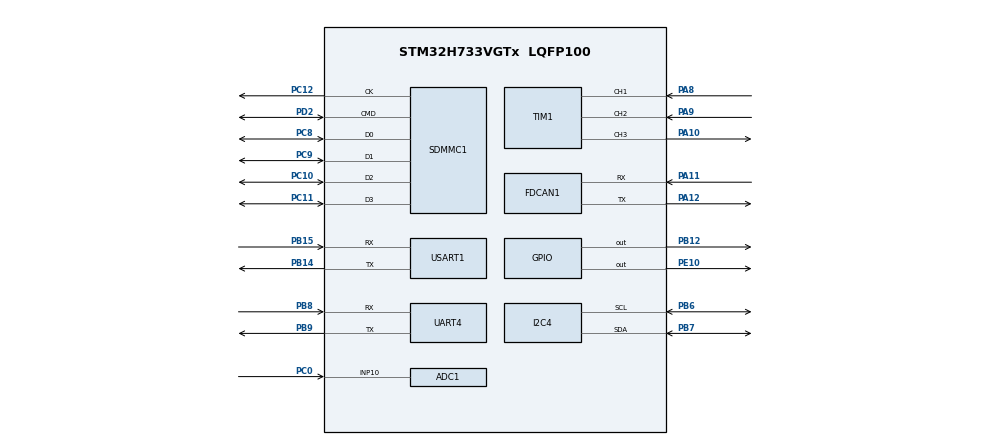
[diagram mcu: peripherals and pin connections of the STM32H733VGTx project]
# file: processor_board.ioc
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ADC1.Channel-1\#ChannelRegularConversion=ADC_CHANNEL_10
ADC1.NbrOfConversion=1
ADC1.NbrOfConversionFlag=1
ADC1.OffsetNumber-1\#ChannelRegularConversion=ADC_OFFSET_NONE
ADC1.OffsetSignedSaturation-1\#ChannelRegularConversion=DISABLE
ADC1.Rank-1\#ChannelRegularConversion=1
ADC1.SamplingTime-1\#ChannelRegularConversion=ADC_SAMPLETIME_1CYCLE_5
ADC1.master=1
Dma.Request0=USART1_RX
Dma.USART1_RX.0.Direction=DMA_PERIPH_TO_MEMORY
Dma.USART1_RX.0.EventEnable=DISABLE
Dma.USART1_RX.0.FIFOMode=DMA_FIFOMODE_DISABLE
Dma.USART1_RX.0.Instance=DMA1_Stream0
Dma.USART1_RX.0.MemDataAlignment=DMA_MDATAALIGN_BYTE
Dma.USART1_RX.0.MemInc=DMA_MINC_ENABLE
Dma.USART1_RX.0.Mode=DMA_NORMAL
Dma.USART1_RX.0.PeriphDataAlignment=DMA_PDATAALIGN_BYTE
Dma.USART1_RX.0.PeriphInc=DMA_PINC_DISABLE
Dma.USART1_RX.0.Polarity=HAL_DMAMUX_REQ_GEN_RISING
Dma.USART1_RX.0.Priority=DMA_PRIORITY_LOW
Dma.USART1_RX.0.RequestNumber=1
Dma.USART1_RX.0.SignalID=NONE
Dma.USART1_RX.0.SyncEnable=DISABLE
Dma.USART1_RX.0.SyncPolarity=HAL_DMAMUX_SYNC_NO_EVENT
Dma.USART1_RX.0.SyncRequestNumber=1
Dma.USART1_RX.0.SyncSignalID=NONE
FDCAN1.CalculateBaudRateNominal=1500000
FDCAN1.CalculateTimeBitNominal=666
FDCAN1.CalculateTimeQuantumNominal=83.33333333333333
FDCAN1.DataPrescaler=4
FDCAN1.DataSyncJumpWidth=4
FDCAN1.DataTimeSeg1=4
FDCAN1.DataTimeSeg2=3
FDCAN1.NominalPrescaler=4
FDCAN1.NominalSyncJumpWidth=4
FDCAN1.NominalTimeSeg1=4
FDCAN1.NominalTimeSeg2=3
FDCAN1.RxFifo0ElmtsNbr=64
FDCAN1.StdFiltersNbr=0
FDCAN1.TxEventsNbr=32
FDCAN1.TxFifoQueueElmtsNbr=32
FREERTOS.INCLUDE_xEventGroupSetBitFromISR=1
FREERTOS.Tasks01=defaultTaskaaa,24,512,StartDefaultTask,Default,NULL,Dynamic,NULL,NULL
FREERTOS.configCHECK_FOR_STACK_OVERFLOW=1
FREERTOS.configENABLE_FPU=1
FREERTOS.configTIMER_TASK_PRIORITY=55
FREERTOS.configTOTAL_HEAP_SIZE=131072
FREERTOS.configUSE_NEWLIB_REENTRANT=0
I2C4.Timing=0x009095E1
Mcu.Family=STM32H7
Mcu.Name=STM32H733VGTx
Mcu.Package=LQFP100
NVIC.DMA1_Stream0_IRQn=true\:5\:0\:false\:false\:true\:true\:false\:true\:true
NVIC.FDCAN1_IT0_IRQn=true\:5\:0\:false\:false\:true\:true\:true\:true\:true
NVIC.I2C4_ER_IRQn=true\:5\:0\:false\:false\:true\:true\:true\:true\:true
NVIC.I2C4_EV_IRQn=true\:5\:0\:false\:false\:true\:true\:true\:true\:true
NVIC.PriorityGroup=NVIC_PRIORITYGROUP_4
NVIC.SDMMC1_IRQn=true\:5\:0\:false\:false\:true\:true\:true\:true\:true
NVIC.TIM6_DAC_IRQn=true\:15\:0\:false\:false\:true\:false\:false\:true\:true
NVIC.TimeBase=TIM6_DAC_IRQn
NVIC.TimeBaseIP=TIM6
NVIC.USART1_IRQn=true\:5\:0\:false\:false\:true\:true\:true\:true\:true
PA10.Signal=S_TIM1_CH3
PA11.GPIO_Speed=GPIO_SPEED_FREQ_LOW
PA11.Mode=FDCAN_Activate
PA11.Signal=FDCAN1_RX
PA12.Mode=FDCAN_Activate
PA12.Signal=FDCAN1_TX
PA13(JTMS/SWDIO).Mode=Serial_Wire
PA13(JTMS/SWDIO).Signal=DEBUG_JTMS-SWDIO
PA14(JTCK/SWCLK).Mode=Serial_Wire
PA14(JTCK/SWCLK).Signal=DEBUG_JTCK-SWCLK
PA8.Signal=S_TIM1_CH1
PA9.Signal=S_TIM1_CH2
PB12.Signal=GPIO_Output
PB14.Mode=Asynchronous
PB14.Signal=USART1_TX
PB15.Mode=Asynchronous
PB15.Signal=USART1_RX
PB6.Mode=I2C
PB6.Signal=I2C4_SCL
PB7.Mode=I2C
PB7.Signal=I2C4_SDA
PB8.Mode=Asynchronous
PB8.Signal=UART4_RX
PB9.Mode=Asynchronous
PB9.Signal=UART4_TX
PC0.Signal=ADCx_INP10
PC10.Mode=SD_4_bits_Wide_bus
PC10.Signal=SDMMC1_D2
PC11.Mode=SD_4_bits_Wide_bus
PC11.Signal=SDMMC1_D3
PC12.Mode=SD_4_bits_Wide_bus
PC12.Signal=SDMMC1_CK
PC8.Mode=SD_4_bits_Wide_bus
PC8.Signal=SDMMC1_D0
PC9.Mode=SD_4_bits_Wide_bus
PC9.Signal=SDMMC1_D1
PD2.Mode=SD_4_bits_Wide_bus
PD2.Signal=SDMMC1_CMD
PE10.Signal=GPIO_Output
PH0-OSC_IN.Mode=HSE-External-Clock-Source
PH0-OSC_IN.Signal=RCC_OSC_IN
ProjectManager.HeapSize=0x200
ProjectManager.StackSize=0x400
ProjectManager.TargetToolchain=STM32CubeIDE
RCC.ADCFreq_Value=38400000
RCC.APB1Freq_Value=96000000
RCC.APB2Freq_Value=96000000
RCC.APB3Freq_Value=96000000
RCC.APB4Freq_Value=96000000
RCC.CortexFreq_Value=192000000
RCC.D1PPRE=RCC_APB3_DIV2
RCC.D2PPRE1=RCC_APB1_DIV2
RCC.D2PPRE2=RCC_APB2_DIV2
RCC.D3PPRE=RCC_APB4_DIV2
RCC.DIVM1=1
RCC.DIVM2=1
RCC.DIVM3=1
RCC.DIVN1=48
RCC.DIVN2=48
RCC.DIVN3=48
RCC.DIVP1=1
RCC.DIVP2=5
RCC.DIVQ1=3
RCC.DIVQ2=4
RCC.DIVQ3=5
RCC.DIVR1=4
RCC.DIVR3=5
RCC.FDCANCLockSelection=RCC_FDCANCLKSOURCE_PLL2
RCC.HCLKFreq_Value=192000000
RCC.HSE_VALUE=4000000
RCC.I2C4CLockSelection=RCC_I2C4CLKSOURCE_PLL3
RCC.PLL2FRACN=0
RCC.PLL3FRACN=0
RCC.PLLFRACN=0
RCC.PLLSourceVirtual=RCC_PLLSOURCE_HSE
RCC.RCC_RTC_Clock_Source_FROM_HSE=RCC_RTCCLKSOURCE_HSE_DIV32
RCC.RTCClockSelection=RCC_RTCCLKSOURCE_HSE_DIV32
RCC.SYSCLKFreq_VALUE=192000000
RCC.SYSCLKSource=RCC_SYSCLKSOURCE_PLLCLK
RCC.USART16CLockSelection=RCC_USART16910CLKSOURCE_PLL3
RCC.USART234578CLockSelection=RCC_USART234578CLKSOURCE_PLL3
RCC.USBFreq_Value=64000000
SH.ADCx_INP10.0=ADC1_INP10,IN10-Single-Ended
SH.S_TIM1_CH1.0=TIM1_CH1,Input_Capture1_from_TI1
SH.S_TIM1_CH2.0=TIM1_CH2,Input_Capture2_from_TI2
SH.S_TIM1_CH3.0=TIM1_CH3,PWM Generation3 CH3
TIM1.Channel-Input_Capture1_from_TI1=TIM_CHANNEL_1
TIM1.Channel-Input_Capture2_from_TI2=TIM_CHANNEL_2
TIM1.Channel-PWM\ Generation3\ CH3=TIM_CHANNEL_3
TIM2.Prescaler=12500
UART4.SwapParam=UART_ADVFEATURE_SWAP_ENABLE
USART1.OverrunDisableParam=ADVFEATURE_OVERRUN_DISABLE
USART1.VirtualMode-Asynchronous=VM_ASYNC
VP_CORDIC_VS_CORDIC.Mode=CORDIC_Activate
VP_FATFS_VS_SDIO.Mode=SDIO
VP_FMAC_VS_FMAC.Mode=FMAC_Activate
VP_FREERTOS_VS_CMSIS_V2.Mode=CMSIS_V2
VP_MEMORYMAP_VS_MEMORYMAP.Mode=CurAppReg
VP_RTC_VS_RTC_Activate.Mode=RTC_Enabled
VP_SYS_VS_tim6.Mode=TIM6
VP_TIM1_VS_ClockSourceINT.Mode=Internal
VP_TIM2_VS_ClockSourceINT.Mode=Internal
VREF+.Mode=InternalMode
VREF+.Signal=VREFBUF_OUT
board=custom

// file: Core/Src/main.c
/* USER CODE BEGIN Header */
/**
  ******************************************************************************
  * @file           : main.c
  * @brief          : Main program body
  ******************************************************************************
  * @attention
  *
  * Copyright (c) 2024 STMicroelectronics.
  * All rights reserved.
  *
  * This software is licensed under terms that can be found in the LICENSE file
  * in the root directory of this software component.
  * If no LICENSE file comes with this software, it is provided AS-IS.
  *
  ******************************************************************************
  */
/* USER CODE END Header */
#include "main.h"
#include "cmsis_os.h"
#include "fatfs.h"

/* USER CODE BEGIN Includes */
#include "printf.h"
//#include "canlib.h"
#include "millis.h"
//#include "ICM-20948.h"

#include "log.h"
//#include "controller.h"
//#include "flight_phase.h"
//#include "health_checks.h"
//#include "state_estimation.h"
//#include "trajectory.h"
#include "can_handler.h"
#include "otits.h"
//#include "sdmmc.h"
//#include "vn_handler.h"

#include "simulink_handler.h"
/* USER CODE END Includes */

/* USER CODE BEGIN PD */
#define DEFAULT_STACKDEPTH_WORDS 128 * 4
/* USER CODE END PD */

ADC_HandleTypeDef hadc1;

CORDIC_HandleTypeDef hcordic;

FDCAN_HandleTypeDef hfdcan1;

FMAC_HandleTypeDef hfmac;

I2C_HandleTypeDef hi2c4;

RTC_HandleTypeDef hrtc;

SD_HandleTypeDef hsd1;

TIM_HandleTypeDef htim1;
TIM_HandleTypeDef htim2;

UART_HandleTypeDef huart4;
UART_HandleTypeDef huart1;
DMA_HandleTypeDef hdma_usart1_rx;

/* Definitions for defaultTask */
osThreadId_t defaultTaskHandle;
const osThreadAttr_t defaultTask_attributes = {
  .name = "defaultTask",
  .stack_size = 512 * 4,
  .priority = (osPriority_t) osPriorityNormal,
};
/* USER CODE BEGIN PV */
uint32_t idx;

//Task handles
TaskHandle_t logTaskhandle = NULL;
TaskHandle_t VNTaskHandle = NULL;
TaskHandle_t trajectoryTaskHandle = NULL;
TaskHandle_t stateEstTaskHandle = NULL;
TaskHandle_t canhandlerhandle = NULL;
TaskHandle_t healthChecksTaskHandle = NULL;
TaskHandle_t controllerHandle = NULL;
TaskHandle_t flightPhaseHandle = NULL;
TaskHandle_t oTITSHandle = NULL;
TaskHandle_t updateModelHandle = NULL;

/* USER CODE END PV */

void SystemClock_Config(void);
void PeriphCommonClock_Config(void);
static void MX_GPIO_Init(void);
static void MX_DMA_Init(void);
static void MX_CORDIC_Init(void);
static void MX_FDCAN1_Init(void);
static void MX_FMAC_Init(void);
static void MX_I2C4_Init(void);
static void MX_RTC_Init(void);
static void MX_SDMMC1_SD_Init(void);
static void MX_UART4_Init(void);
static void MX_TIM1_Init(void);
static void MX_ADC1_Init(void);
static void MX_USART1_UART_Init(void);
static void MX_TIM2_Init(void);
void StartDefaultTask(void *argument);

/* USER CODE BEGIN 0 */
Otits_Result_t test_defaultTaskPass() {
	Otits_Result_t res;
	res.info = "this should pass";
	res.outcome = TEST_OUTCOME_PASSED;
	return res;
}

Otits_Result_t test_defaultTaskFail() {
	Otits_Result_t res;
	res.info = "this should fail";
	res.outcome = TEST_OUTCOME_FAILED;
	return res;
}

Otits_Result_t test_taskStackUsage() {
    Otits_Result_t res;
    const int numTasks = 9;
    int stackWatermarks[numTasks];

    stackWatermarks[0] = uxTaskGetStackHighWaterMark(logTaskhandle);
    stackWatermarks[1] = uxTaskGetStackHighWaterMark(VNTaskHandle);
    stackWatermarks[2] = uxTaskGetStackHighWaterMark(trajectoryTaskHandle);
    stackWatermarks[3] = uxTaskGetStackHighWaterMark(stateEstTaskHandle);
    stackWatermarks[4] = uxTaskGetStackHighWaterMark(canhandlerhandle);
    stackWatermarks[5] = uxTaskGetStackHighWaterMark(healthChecksTaskHandle);
    stackWatermarks[6] = uxTaskGetStackHighWaterMark(controllerHandle);
    stackWatermarks[7] = uxTaskGetStackHighWaterMark(flightPhaseHandle);
    stackWatermarks[8] = uxTaskGetStackHighWaterMark(oTITSHandle);

    for (int i = 0; i < numTasks; i++) {
        if (stackWatermarks[i] < 50) {
            char info[10];
            snprintf_(info, 10, "low%d", i);
            res.info = info;
            res.outcome = TEST_OUTCOME_FAILED;
            return res;
        } else if (stackWatermarks[i] > 1000) {
            char info[10];
            snprintf_(info, 10, "high%d", i);
            res.info = info;
            res.outcome = TEST_OUTCOME_FAILED;
            return res;
        }
    }

    res.info = "";
    res.outcome = TEST_OUTCOME_PASSED;
    return res;
}

/* USER CODE END 0 */

int main(void)
{

  /* MCU Configuration--------------------------------------------------------*/

  /* Reset of all peripherals, Initializes the Flash interface and the Systick. */
  HAL_Init();

  /* Configure the system clock */
  SystemClock_Config();

/* Configure the peripherals common clocks */
  PeriphCommonClock_Config();

  /* Initialize all configured peripherals */
  MX_GPIO_Init();
  MX_DMA_Init();
  MX_CORDIC_Init();
  MX_FDCAN1_Init();
  MX_FMAC_Init();
  MX_I2C4_Init();
  MX_RTC_Init();
  MX_SDMMC1_SD_Init();
  MX_UART4_Init();
  MX_FATFS_Init();
  MX_TIM1_Init();
  MX_ADC1_Init();
  MX_USART1_UART_Init();
  MX_TIM2_Init();
  /* USER CODE BEGIN 2 */
  HAL_TIM_Base_Start(&htim2);
  /* USER CODE END 2 */

  /* Init scheduler */
  osKernelInitialize();

  /* USER CODE BEGIN RTOS_QUEUES */
  bool initRes = true;
#if USE_ICM == 1
  ICM_20948_init();
#endif
//  initRes &= sdmmcInit();
//  initRes &= logInit();
//  initRes &= trajectory_init();
  initRes &= canHandlerInit(); //create bus queue
//  initRes &= flightPhaseInit();
//  initRes &= healthCheckInit();
//  initRes &= controllerInit();
//  initRes &= state_est_init();
//  initRes &= vn_handler_init();
  	updateModelTaskInit();

  // otits is ifdef guarded within itself so can leave these
  initRes &= otitsRegister(test_defaultTaskPass, TEST_SOURCE_DEFAULT, "DefaultPass");
  initRes &= otitsRegister(test_defaultTaskFail, TEST_SOURCE_DEFAULT, "DefaultFail");
  initRes &= otitsRegister(test_taskStackUsage, TEST_SOURCE_DEFAULT, "StackUsage");

  if (!initRes) {
      Error_Handler();
  }
  /* USER CODE END RTOS_QUEUES */

  /* Create the thread(s) */
  /* creation of defaultTask */
  defaultTaskHandle = osThreadNew(StartDefaultTask, NULL, &defaultTask_attributes);

  /* USER CODE BEGIN RTOS_THREADS */
  /* add threads, ... */
  BaseType_t xReturned = pdPASS;

  //dunno if casting from CMSIS priorities is valid
//  xReturned &= xTaskCreate(vnIMUHandler, "VN Task", 1024, NULL, (UBaseType_t) osPriorityNormal, &VNTaskHandle);
  xReturned &= xTaskCreate(canHandlerTask, "CAN handler", 512, NULL, (UBaseType_t) osPriorityNormal, &canhandlerhandle);
//  xReturned &= xTaskCreate(stateEstTask, "StateEst", 1024, NULL, (UBaseType_t) osPriorityNormal, &stateEstTaskHandle);
//  xReturned &= xTaskCreate(trajectory_task, "traj", 512, NULL, (UBaseType_t) osPriorityNormal, &trajectoryTaskHandle);
//  xReturned &= xTaskCreate(logTask, "Logging", 1024, NULL, (UBaseType_t) osPriorityNormal, &logTaskhandle);
//  xReturned &= xTaskCreate(healthCheckTask, "health checks", 512, NULL, (UBaseType_t) osPriorityNormal, &healthChecksTaskHandle);
//  xReturned &= xTaskCreate(controlTask, "Controller", 512, NULL, (UBaseType_t) osPriorityNormal, &controllerHandle);
//  xReturned &= xTaskCreate(flightPhaseTask, "Flight Phase", 512, NULL, (UBaseType_t) osPriorityNormal, &flightPhaseHandle);
  xReturned &= xTaskCreate(updateModelTask, "simulink", 512, NULL, (UBaseType_t) osPriorityNormal, &updateModelHandle);

#if  defined(TEST_MODE) && defined(DEBUG)
  xReturned &= xTaskCreate(otitsTask, "oTITS", 1024, NULL, (UBaseType_t) osPriorityNormal, &oTITSHandle);
#endif

  if(xReturned != pdPASS)
  {
	  //one or more tasks failed to be created
	  Error_Handler();
  }

  /* USER CODE END RTOS_THREADS */

  /* Start scheduler */
  osKernelStart();

  /* We should never get here as control is now taken by the scheduler */

  /* Infinite loop */
  while (1)
  {

  }
}

void SystemClock_Config(void)
{
  RCC_OscInitTypeDef RCC_OscInitStruct = {0};
  RCC_ClkInitTypeDef RCC_ClkInitStruct = {0};

  /** Supply configuration update enable
  */
  HAL_PWREx_ConfigSupply(PWR_LDO_SUPPLY);

  /** Configure the main internal regulator output voltage
  */
  __HAL_PWR_VOLTAGESCALING_CONFIG(PWR_REGULATOR_VOLTAGE_SCALE0);

  while(!__HAL_PWR_GET_FLAG(PWR_FLAG_VOSRDY)) {}

  /** Initializes the RCC Oscillators according to the specified parameters
  * in the RCC_OscInitTypeDef structure.
  */
  RCC_OscInitStruct.OscillatorType = RCC_OSCILLATORTYPE_HSE;
  RCC_OscInitStruct.HSEState = RCC_HSE_BYPASS;
  RCC_OscInitStruct.PLL.PLLState = RCC_PLL_ON;
  RCC_OscInitStruct.PLL.PLLSource = RCC_PLLSOURCE_HSE;
  RCC_OscInitStruct.PLL.PLLM = 1;
  RCC_OscInitStruct.PLL.PLLN = 125;
  RCC_OscInitStruct.PLL.PLLP = 1;
  RCC_OscInitStruct.PLL.PLLQ = 20;
  RCC_OscInitStruct.PLL.PLLR = 4;
  RCC_OscInitStruct.PLL.PLLRGE = RCC_PLL1VCIRANGE_2;
  RCC_OscInitStruct.PLL.PLLVCOSEL = RCC_PLL1VCOWIDE;
  RCC_OscInitStruct.PLL.PLLFRACN = 0;
  if (HAL_RCC_OscConfig(&RCC_OscInitStruct) != HAL_OK)
  {
    Error_Handler();
  }

  /** Initializes the CPU, AHB and APB buses clocks
  */
  RCC_ClkInitStruct.ClockType = RCC_CLOCKTYPE_HCLK|RCC_CLOCKTYPE_SYSCLK
                              |RCC_CLOCKTYPE_PCLK1|RCC_CLOCKTYPE_PCLK2
                              |RCC_CLOCKTYPE_D3PCLK1|RCC_CLOCKTYPE_D1PCLK1;
  RCC_ClkInitStruct.SYSCLKSource = RCC_SYSCLKSOURCE_PLLCLK;
  RCC_ClkInitStruct.SYSCLKDivider = RCC_SYSCLK_DIV1;
  RCC_ClkInitStruct.AHBCLKDivider = RCC_HCLK_DIV4;
  RCC_ClkInitStruct.APB3CLKDivider = RCC_APB3_DIV2;
  RCC_ClkInitStruct.APB1CLKDivider = RCC_APB1_DIV2;
  RCC_ClkInitStruct.APB2CLKDivider = RCC_APB2_DIV2;
  RCC_ClkInitStruct.APB4CLKDivider = RCC_APB4_DIV2;

  if (HAL_RCC_ClockConfig(&RCC_ClkInitStruct, FLASH_LATENCY_1) != HAL_OK)
  {
    Error_Handler();
  }
}

void PeriphCommonClock_Config(void)
{
  RCC_PeriphCLKInitTypeDef PeriphClkInitStruct = {0};

  /** Initializes the peripherals clock
  */
  PeriphClkInitStruct.PeriphClockSelection = RCC_PERIPHCLK_I2C4|RCC_PERIPHCLK_ADC
                              |RCC_PERIPHCLK_FDCAN|RCC_PERIPHCLK_USART1
                              |RCC_PERIPHCLK_UART4;
  PeriphClkInitStruct.PLL2.PLL2M = 1;
  PeriphClkInitStruct.PLL2.PLL2N = 120;
  PeriphClkInitStruct.PLL2.PLL2P = 20;
  PeriphClkInitStruct.PLL2.PLL2Q = 60;
  PeriphClkInitStruct.PLL2.PLL2R = 2;
  PeriphClkInitStruct.PLL2.PLL2RGE = RCC_PLL2VCIRANGE_2;
  PeriphClkInitStruct.PLL2.PLL2VCOSEL = RCC_PLL2VCOWIDE;
  PeriphClkInitStruct.PLL2.PLL2FRACN = 0;
  PeriphClkInitStruct.PLL3.PLL3M = 2;
  PeriphClkInitStruct.PLL3.PLL3N = 128;
  PeriphClkInitStruct.PLL3.PLL3P = 2;
  PeriphClkInitStruct.PLL3.PLL3Q = 2;
  PeriphClkInitStruct.PLL3.PLL3R = 8;
  PeriphClkInitStruct.PLL3.PLL3RGE = RCC_PLL3VCIRANGE_1;
  PeriphClkInitStruct.PLL3.PLL3VCOSEL = RCC_PLL3VCOWIDE;
  PeriphClkInitStruct.PLL3.PLL3FRACN = 0;
  PeriphClkInitStruct.FdcanClockSelection = RCC_FDCANCLKSOURCE_PLL2;
  PeriphClkInitStruct.Usart234578ClockSelection = RCC_USART234578CLKSOURCE_PLL3;
  PeriphClkInitStruct.Usart16ClockSelection = RCC_USART16910CLKSOURCE_PLL3;
  PeriphClkInitStruct.I2c4ClockSelection = RCC_I2C4CLKSOURCE_PLL3;
  PeriphClkInitStruct.AdcClockSelection = RCC_ADCCLKSOURCE_PLL2;
  if (HAL_RCCEx_PeriphCLKConfig(&PeriphClkInitStruct) != HAL_OK)
  {
    Error_Handler();
  }
}

static void MX_ADC1_Init(void)
{

  ADC_MultiModeTypeDef multimode = {0};
  ADC_ChannelConfTypeDef sConfig = {0};

  /** Common config
  */
  hadc1.Instance = ADC1;
  hadc1.Init.ClockPrescaler = ADC_CLOCK_ASYNC_DIV1;
  hadc1.Init.Resolution = ADC_RESOLUTION_16B;
  hadc1.Init.ScanConvMode = ADC_SCAN_DISABLE;
  hadc1.Init.EOCSelection = ADC_EOC_SINGLE_CONV;
  hadc1.Init.LowPowerAutoWait = DISABLE;
  hadc1.Init.ContinuousConvMode = DISABLE;
  hadc1.Init.NbrOfConversion = 1;
  hadc1.Init.DiscontinuousConvMode = DISABLE;
  hadc1.Init.ExternalTrigConv = ADC_SOFTWARE_START;
  hadc1.Init.ExternalTrigConvEdge = ADC_EXTERNALTRIGCONVEDGE_NONE;
  hadc1.Init.ConversionDataManagement = ADC_CONVERSIONDATA_DR;
  hadc1.Init.Overrun = ADC_OVR_DATA_PRESERVED;
  hadc1.Init.LeftBitShift = ADC_LEFTBITSHIFT_NONE;
  hadc1.Init.OversamplingMode = DISABLE;
  if (HAL_ADC_Init(&hadc1) != HAL_OK)
  {
    Error_Handler();
  }

  /** Configure the ADC multi-mode
  */
  multimode.Mode = ADC_MODE_INDEPENDENT;
  if (HAL_ADCEx_MultiModeConfigChannel(&hadc1, &multimode) != HAL_OK)
  {
    Error_Handler();
  }

  /** Configure Regular Channel
  */
  sConfig.Channel = ADC_CHANNEL_10;
  sConfig.Rank = ADC_REGULAR_RANK_1;
  sConfig.SamplingTime = ADC_SAMPLETIME_1CYCLE_5;
  sConfig.SingleDiff = ADC_SINGLE_ENDED;
  sConfig.OffsetNumber = ADC_OFFSET_NONE;
  sConfig.Offset = 0;
  sConfig.OffsetSignedSaturation = DISABLE;
  if (HAL_ADC_ConfigChannel(&hadc1, &sConfig) != HAL_OK)
  {
    Error_Handler();
  }

}

static void MX_CORDIC_Init(void)
{

  hcordic.Instance = CORDIC;
  if (HAL_CORDIC_Init(&hcordic) != HAL_OK)
  {
    Error_Handler();
  }

}

static void MX_FDCAN1_Init(void)
{

  hfdcan1.Instance = FDCAN1;
  hfdcan1.Init.FrameFormat = FDCAN_FRAME_CLASSIC;
  hfdcan1.Init.Mode = FDCAN_MODE_NORMAL;
  hfdcan1.Init.AutoRetransmission = DISABLE;
  hfdcan1.Init.TransmitPause = DISABLE;
  hfdcan1.Init.ProtocolException = DISABLE;
  hfdcan1.Init.NominalPrescaler = 4;
  hfdcan1.Init.NominalSyncJumpWidth = 4;
  hfdcan1.Init.NominalTimeSeg1 = 4;
  hfdcan1.Init.NominalTimeSeg2 = 3;
  hfdcan1.Init.DataPrescaler = 4;
  hfdcan1.Init.DataSyncJumpWidth = 4;
  hfdcan1.Init.DataTimeSeg1 = 4;
  hfdcan1.Init.DataTimeSeg2 = 3;
  hfdcan1.Init.MessageRAMOffset = 0;
  hfdcan1.Init.StdFiltersNbr = 0;
  hfdcan1.Init.ExtFiltersNbr = 0;
  hfdcan1.Init.RxFifo0ElmtsNbr = 64;
  hfdcan1.Init.RxFifo0ElmtSize = FDCAN_DATA_BYTES_8;
  hfdcan1.Init.RxFifo1ElmtsNbr = 0;
  hfdcan1.Init.RxFifo1ElmtSize = FDCAN_DATA_BYTES_8;
  hfdcan1.Init.RxBuffersNbr = 0;
  hfdcan1.Init.RxBufferSize = FDCAN_DATA_BYTES_8;
  hfdcan1.Init.TxEventsNbr = 32;
  hfdcan1.Init.TxBuffersNbr = 0;
  hfdcan1.Init.TxFifoQueueElmtsNbr = 32;
  hfdcan1.Init.TxFifoQueueMode = FDCAN_TX_FIFO_OPERATION;
  hfdcan1.Init.TxElmtSize = FDCAN_DATA_BYTES_8;
  if (HAL_FDCAN_Init(&hfdcan1) != HAL_OK)
  {
    Error_Handler();
  }

}

static void MX_FMAC_Init(void)
{

  hfmac.Instance = FMAC;
  if (HAL_FMAC_Init(&hfmac) != HAL_OK)
  {
    Error_Handler();
  }

}

static void MX_I2C4_Init(void)
{

  hi2c4.Instance = I2C4;
  hi2c4.Init.Timing = 0x00707CBB;
  hi2c4.Init.OwnAddress1 = 0;
  hi2c4.Init.AddressingMode = I2C_ADDRESSINGMODE_7BIT;
  hi2c4.Init.DualAddressMode = I2C_DUALADDRESS_DISABLE;
  hi2c4.Init.OwnAddress2 = 0;
  hi2c4.Init.OwnAddress2Masks = I2C_OA2_NOMASK;
  hi2c4.Init.GeneralCallMode = I2C_GENERALCALL_DISABLE;
  hi2c4.Init.NoStretchMode = I2C_NOSTRETCH_DISABLE;
  if (HAL_I2C_Init(&hi2c4) != HAL_OK)
  {
    Error_Handler();
  }

  /** Configure Analogue filter
  */
  if (HAL_I2CEx_ConfigAnalogFilter(&hi2c4, I2C_ANALOGFILTER_ENABLE) != HAL_OK)
  {
    Error_Handler();
  }

  /** Configure Digital filter
  */
  if (HAL_I2CEx_ConfigDigitalFilter(&hi2c4, 0) != HAL_OK)
  {
    Error_Handler();
  }

}

static void MX_RTC_Init(void)
{

  /** Initialize RTC Only
  */
  hrtc.Instance = RTC;
  hrtc.Init.HourFormat = RTC_HOURFORMAT_24;
  hrtc.Init.AsynchPrediv = 127;
  hrtc.Init.SynchPrediv = 255;
  hrtc.Init.OutPut = RTC_OUTPUT_DISABLE;
  hrtc.Init.OutPutPolarity = RTC_OUTPUT_POLARITY_HIGH;
  hrtc.Init.OutPutType = RTC_OUTPUT_TYPE_OPENDRAIN;
  hrtc.Init.OutPutRemap = RTC_OUTPUT_REMAP_NONE;
  if (HAL_RTC_Init(&hrtc) != HAL_OK)
  {
    Error_Handler();
  }

}

static void MX_SDMMC1_SD_Init(void)
{

  hsd1.Instance = SDMMC1;
  hsd1.Init.ClockEdge = SDMMC_CLOCK_EDGE_RISING;
  hsd1.Init.ClockPowerSave = SDMMC_CLOCK_POWER_SAVE_DISABLE;
  hsd1.Init.BusWide = SDMMC_BUS_WIDE_4B;
  hsd1.Init.HardwareFlowControl = SDMMC_HARDWARE_FLOW_CONTROL_DISABLE;
  hsd1.Init.ClockDiv = 0;

}

static void MX_TIM1_Init(void)
{

  TIM_ClockConfigTypeDef sClockSourceConfig = {0};
  TIM_MasterConfigTypeDef sMasterConfig = {0};
  TIM_IC_InitTypeDef sConfigIC = {0};
  TIM_OC_InitTypeDef sConfigOC = {0};
  TIM_BreakDeadTimeConfigTypeDef sBreakDeadTimeConfig = {0};

  htim1.Instance = TIM1;
  htim1.Init.Prescaler = 0;
  htim1.Init.CounterMode = TIM_COUNTERMODE_UP;
  htim1.Init.Period = 65535;
  htim1.Init.ClockDivision = TIM_CLOCKDIVISION_DIV1;
  htim1.Init.RepetitionCounter = 0;
  htim1.Init.AutoReloadPreload = TIM_AUTORELOAD_PRELOAD_DISABLE;
  if (HAL_TIM_Base_Init(&htim1) != HAL_OK)
  {
    Error_Handler();
  }
  sClockSourceConfig.ClockSource = TIM_CLOCKSOURCE_INTERNAL;
  if (HAL_TIM_ConfigClockSource(&htim1, &sClockSourceConfig) != HAL_OK)
  {
    Error_Handler();
  }
  if (HAL_TIM_IC_Init(&htim1) != HAL_OK)
  {
    Error_Handler();
  }
  if (HAL_TIM_PWM_Init(&htim1) != HAL_OK)
  {
    Error_Handler();
  }
  sMasterConfig.MasterOutputTrigger = TIM_TRGO_RESET;
  sMasterConfig.MasterOutputTrigger2 = TIM_TRGO2_RESET;
  sMasterConfig.MasterSlaveMode = TIM_MASTERSLAVEMODE_DISABLE;
  if (HAL_TIMEx_MasterConfigSynchronization(&htim1, &sMasterConfig) != HAL_OK)
  {
    Error_Handler();
  }
  sConfigIC.ICPolarity = TIM_INPUTCHANNELPOLARITY_RISING;
  sConfigIC.ICSelection = TIM_ICSELECTION_DIRECTTI;
  sConfigIC.ICPrescaler = TIM_ICPSC_DIV1;
  sConfigIC.ICFilter = 0;
  if (HAL_TIM_IC_ConfigChannel(&htim1, &sConfigIC, TIM_CHANNEL_1) != HAL_OK)
  {
    Error_Handler();
  }
  if (HAL_TIM_IC_ConfigChannel(&htim1, &sConfigIC, TIM_CHANNEL_2) != HAL_OK)
  {
    Error_Handler();
  }
  sConfigOC.OCMode = TIM_OCMODE_PWM1;
  sConfigOC.Pulse = 0;
  sConfigOC.OCPolarity = TIM_OCPOLARITY_HIGH;
  sConfigOC.OCNPolarity = TIM_OCNPOLARITY_HIGH;
  sConfigOC.OCFastMode = TIM_OCFAST_DISABLE;
  sConfigOC.OCIdleState = TIM_OCIDLESTATE_RESET;
  sConfigOC.OCNIdleState = TIM_OCNIDLESTATE_RESET;
  if (HAL_TIM_PWM_ConfigChannel(&htim1, &sConfigOC, TIM_CHANNEL_3) != HAL_OK)
  {
    Error_Handler();
  }
  sBreakDeadTimeConfig.OffStateRunMode = TIM_OSSR_DISABLE;
  sBreakDeadTimeConfig.OffStateIDLEMode = TIM_OSSI_DISABLE;
  sBreakDeadTimeConfig.LockLevel = TIM_LOCKLEVEL_OFF;
  sBreakDeadTimeConfig.DeadTime = 0;
  sBreakDeadTimeConfig.BreakState = TIM_BREAK_DISABLE;
  sBreakDeadTimeConfig.BreakPolarity = TIM_BREAKPOLARITY_HIGH;
  sBreakDeadTimeConfig.BreakFilter = 0;
  sBreakDeadTimeConfig.Break2State = TIM_BREAK2_DISABLE;
  sBreakDeadTimeConfig.Break2Polarity = TIM_BREAK2POLARITY_HIGH;
  sBreakDeadTimeConfig.Break2Filter = 0;
  sBreakDeadTimeConfig.AutomaticOutput = TIM_AUTOMATICOUTPUT_DISABLE;
  if (HAL_TIMEx_ConfigBreakDeadTime(&htim1, &sBreakDeadTimeConfig) != HAL_OK)
  {
    Error_Handler();
  }
  HAL_TIM_MspPostInit(&htim1);

}

static void MX_TIM2_Init(void)
{

  TIM_ClockConfigTypeDef sClockSourceConfig = {0};
  TIM_MasterConfigTypeDef sMasterConfig = {0};

  htim2.Instance = TIM2;
  htim2.Init.Prescaler = 12500;
  htim2.Init.CounterMode = TIM_COUNTERMODE_UP;
  htim2.Init.Period = 4294967295;
  htim2.Init.ClockDivision = TIM_CLOCKDIVISION_DIV1;
  htim2.Init.AutoReloadPreload = TIM_AUTORELOAD_PRELOAD_DISABLE;
  if (HAL_TIM_Base_Init(&htim2) != HAL_OK)
  {
    Error_Handler();
  }
  sClockSourceConfig.ClockSource = TIM_CLOCKSOURCE_INTERNAL;
  if (HAL_TIM_ConfigClockSource(&htim2, &sClockSourceConfig) != HAL_OK)
  {
    Error_Handler();
  }
  sMasterConfig.MasterOutputTrigger = TIM_TRGO_RESET;
  sMasterConfig.MasterSlaveMode = TIM_MASTERSLAVEMODE_DISABLE;
  if (HAL_TIMEx_MasterConfigSynchronization(&htim2, &sMasterConfig) != HAL_OK)
  {
    Error_Handler();
  }

}

static void MX_UART4_Init(void)
{

  huart4.Instance = UART4;
  huart4.Init.BaudRate = 115200;
  huart4.Init.WordLength = UART_WORDLENGTH_8B;
  huart4.Init.StopBits = UART_STOPBITS_1;
  huart4.Init.Parity = UART_PARITY_NONE;
  huart4.Init.Mode = UART_MODE_TX_RX;
  huart4.Init.HwFlowCtl = UART_HWCONTROL_NONE;
  huart4.Init.OverSampling = UART_OVERSAMPLING_16;
  huart4.Init.OneBitSampling = UART_ONE_BIT_SAMPLE_DISABLE;
  huart4.Init.ClockPrescaler = UART_PRESCALER_DIV1;
  huart4.AdvancedInit.AdvFeatureInit = UART_ADVFEATURE_SWAP_INIT;
  huart4.AdvancedInit.Swap = UART_ADVFEATURE_SWAP_ENABLE;
  if (HAL_UART_Init(&huart4) != HAL_OK)
  {
    Error_Handler();
  }
  if (HAL_UARTEx_SetTxFifoThreshold(&huart4, UART_TXFIFO_THRESHOLD_1_8) != HAL_OK)
  {
    Error_Handler();
  }
  if (HAL_UARTEx_SetRxFifoThreshold(&huart4, UART_RXFIFO_THRESHOLD_1_8) != HAL_OK)
  {
    Error_Handler();
  }
  if (HAL_UARTEx_DisableFifoMode(&huart4) != HAL_OK)
  {
    Error_Handler();
  }

}

static void MX_USART1_UART_Init(void)
{

  huart1.Instance = USART1;
  huart1.Init.BaudRate = 115200;
  huart1.Init.WordLength = UART_WORDLENGTH_8B;
  huart1.Init.StopBits = UART_STOPBITS_1;
  huart1.Init.Parity = UART_PARITY_NONE;
  huart1.Init.Mode = UART_MODE_TX_RX;
  huart1.Init.HwFlowCtl = UART_HWCONTROL_NONE;
  huart1.Init.OverSampling = UART_OVERSAMPLING_16;
  huart1.Init.OneBitSampling = UART_ONE_BIT_SAMPLE_DISABLE;
  huart1.Init.ClockPrescaler = UART_PRESCALER_DIV1;
  huart1.AdvancedInit.AdvFeatureInit = UART_ADVFEATURE_RXOVERRUNDISABLE_INIT;
  huart1.AdvancedInit.OverrunDisable = UART_ADVFEATURE_OVERRUN_DISABLE;
  if (HAL_UART_Init(&huart1) != HAL_OK)
  {
    Error_Handler();
  }
  if (HAL_UARTEx_SetTxFifoThreshold(&huart1, UART_TXFIFO_THRESHOLD_1_8) != HAL_OK)
  {
    Error_Handler();
  }
  if (HAL_UARTEx_SetRxFifoThreshold(&huart1, UART_RXFIFO_THRESHOLD_1_8) != HAL_OK)
  {
    Error_Handler();
  }
  if (HAL_UARTEx_DisableFifoMode(&huart1) != HAL_OK)
  {
    Error_Handler();
  }

}

static void MX_DMA_Init(void)
{

  /* DMA controller clock enable */
  __HAL_RCC_DMA1_CLK_ENABLE();

  /* DMA interrupt init */
  /* DMA1_Stream0_IRQn interrupt configuration */
  HAL_NVIC_SetPriority(DMA1_Stream0_IRQn, 5, 0);
  HAL_NVIC_EnableIRQ(DMA1_Stream0_IRQn);

}

static void MX_GPIO_Init(void)
{
  GPIO_InitTypeDef GPIO_InitStruct = {0};

  /* GPIO Ports Clock Enable */
  __HAL_RCC_GPIOE_CLK_ENABLE();
  __HAL_RCC_GPIOC_CLK_ENABLE();
  __HAL_RCC_GPIOH_CLK_ENABLE();
  __HAL_RCC_GPIOA_CLK_ENABLE();
  __HAL_RCC_GPIOB_CLK_ENABLE();
  __HAL_RCC_GPIOD_CLK_ENABLE();

  /*Configure GPIO pin Output Level */
  HAL_GPIO_WritePin(GPIOE, GPIO_PIN_9|GPIO_PIN_10, GPIO_PIN_RESET);

  /*Configure GPIO pin Output Level */
  HAL_GPIO_WritePin(GPIOB, GPIO_PIN_12, GPIO_PIN_RESET);

  /*Configure GPIO pins : PE2 PE3 PE4 PE5
                           PE6 PE7 PE8 PE11
                           PE12 PE13 PE14 PE15
                           PE0 PE1 */
  GPIO_InitStruct.Pin = GPIO_PIN_2|GPIO_PIN_3|GPIO_PIN_4|GPIO_PIN_5
                          |GPIO_PIN_6|GPIO_PIN_7|GPIO_PIN_8|GPIO_PIN_11
                          |GPIO_PIN_12|GPIO_PIN_13|GPIO_PIN_14|GPIO_PIN_15
                          |GPIO_PIN_0|GPIO_PIN_1;
  GPIO_InitStruct.Mode = GPIO_MODE_ANALOG;
  GPIO_InitStruct.Pull = GPIO_NOPULL;
  HAL_GPIO_Init(GPIOE, &GPIO_InitStruct);

  /*Configure GPIO pins : PC13 PC14 PC15 PC1
                           PC2 PC3 PC4 PC5
                           PC6 PC7 */
  GPIO_InitStruct.Pin = GPIO_PIN_13|GPIO_PIN_14|GPIO_PIN_15|GPIO_PIN_1
                          |GPIO_PIN_2|GPIO_PIN_3|GPIO_PIN_4|GPIO_PIN_5
                          |GPIO_PIN_6|GPIO_PIN_7;
  GPIO_InitStruct.Mode = GPIO_MODE_ANALOG;
  GPIO_InitStruct.Pull = GPIO_NOPULL;
  HAL_GPIO_Init(GPIOC, &GPIO_InitStruct);

  /*Configure GPIO pin : PH1 */
  GPIO_InitStruct.Pin = GPIO_PIN_1;
  GPIO_InitStruct.Mode = GPIO_MODE_ANALOG;
  GPIO_InitStruct.Pull = GPIO_NOPULL;
  HAL_GPIO_Init(GPIOH, &GPIO_InitStruct);

  /*Configure GPIO pins : PA0 PA1 PA2 PA3
                           PA4 PA5 PA6 PA7
                           PA15 */
  GPIO_InitStruct.Pin = GPIO_PIN_0|GPIO_PIN_1|GPIO_PIN_2|GPIO_PIN_3
                          |GPIO_PIN_4|GPIO_PIN_5|GPIO_PIN_6|GPIO_PIN_7
                          |GPIO_PIN_15;
  GPIO_InitStruct.Mode = GPIO_MODE_ANALOG;
  GPIO_InitStruct.Pull = GPIO_NOPULL;
  HAL_GPIO_Init(GPIOA, &GPIO_InitStruct);

  /*Configure GPIO pins : PB0 PB1 PB2 PB10
                           PB11 PB13 PB3 PB4
                           PB5 */
  GPIO_InitStruct.Pin = GPIO_PIN_0|GPIO_PIN_1|GPIO_PIN_2|GPIO_PIN_10
                          |GPIO_PIN_11|GPIO_PIN_13|GPIO_PIN_3|GPIO_PIN_4
                          |GPIO_PIN_5;
  GPIO_InitStruct.Mode = GPIO_MODE_ANALOG;
  GPIO_InitStruct.Pull = GPIO_NOPULL;
  HAL_GPIO_Init(GPIOB, &GPIO_InitStruct);

  /*Configure GPIO pins : PE9 PE10 */
  GPIO_InitStruct.Pin = GPIO_PIN_9|GPIO_PIN_10;
  GPIO_InitStruct.Mode = GPIO_MODE_OUTPUT_PP;
  GPIO_InitStruct.Pull = GPIO_NOPULL;
  GPIO_InitStruct.Speed = GPIO_SPEED_FREQ_LOW;
  HAL_GPIO_Init(GPIOE, &GPIO_InitStruct);

  /*Configure GPIO pin : PB12 */
  GPIO_InitStruct.Pin = GPIO_PIN_12;
  GPIO_InitStruct.Mode = GPIO_MODE_OUTPUT_PP;
  GPIO_InitStruct.Pull = GPIO_NOPULL;
  GPIO_InitStruct.Speed = GPIO_SPEED_FREQ_LOW;
  HAL_GPIO_Init(GPIOB, &GPIO_InitStruct);

  /*Configure GPIO pins : PD8 PD9 PD10 PD11
                           PD12 PD13 PD14 PD15
                           PD0 PD1 PD3 PD4
                           PD5 PD6 PD7 */
  GPIO_InitStruct.Pin = GPIO_PIN_8|GPIO_PIN_9|GPIO_PIN_10|GPIO_PIN_11
                          |GPIO_PIN_12|GPIO_PIN_13|GPIO_PIN_14|GPIO_PIN_15
                          |GPIO_PIN_0|GPIO_PIN_1|GPIO_PIN_3|GPIO_PIN_4
                          |GPIO_PIN_5|GPIO_PIN_6|GPIO_PIN_7;
  GPIO_InitStruct.Mode = GPIO_MODE_ANALOG;
  GPIO_InitStruct.Pull = GPIO_NOPULL;
  HAL_GPIO_Init(GPIOD, &GPIO_InitStruct);

}

void StartDefaultTask(void *argument)
{
  /* USER CODE BEGIN 5 */
	/* Infinite loop */
	int test_in = 0;

	for(;;)
	{
		test_in = (test_in + 1) % 11; //redneck saw wave
		rtU_thisIsAnInput = (double) (test_in - 5);
		printf_("PID output: %f", rtY_thisIsAnOutput);

		HAL_GPIO_TogglePin(GPIOB, GPIO_PIN_12);
		vTaskDelay(1000);
	}
  /* USER CODE END 5 */
}

void HAL_TIM_PeriodElapsedCallback(TIM_HandleTypeDef *htim)
{
  if (htim->Instance == TIM6) {
    HAL_IncTick();
  }
}

void Error_Handler(void)
{
  /* USER CODE BEGIN Error_Handler_Debug */
  /* User can add his own implementation to report the HAL error return state */
  __disable_irq();
  while (1)
  {
	  //TODO: Report error condition over BUS, attempt to command airbrakes closed
  }
  /* USER CODE END Error_Handler_Debug */
}

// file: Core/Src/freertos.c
/* USER CODE BEGIN Header */
/**
  ******************************************************************************
  * File Name          : freertos.c
  * Description        : Code for freertos applications
  ******************************************************************************
  * @attention
  *
  * Copyright (c) 2024 STMicroelectronics.
  * All rights reserved.
  *
  * This software is licensed under terms that can be found in the LICENSE file
  * in the root directory of this software component.
  * If no LICENSE file comes with this software, it is provided AS-IS.
  *
  ******************************************************************************
  */
/* USER CODE END Header */

#include "FreeRTOS.h"
#include "task.h"
#include "main.h"

/* Hook prototypes */
void vApplicationStackOverflowHook(xTaskHandle xTask, signed char *pcTaskName);

/* USER CODE BEGIN 4 */
void vApplicationStackOverflowHook(xTaskHandle xTask, signed char *pcTaskName)
{
   /* Run time stack overflow checking is performed if
   configCHECK_FOR_STACK_OVERFLOW is defined to 1 or 2. This hook function is
   called if a stack overflow is detected. */
    while (1) {

    }
}
/* USER CODE END 4 */

/* USER CODE BEGIN Application */
__weak void configureTimerForRunTimeStats(void)
{
}

extern volatile unsigned long ulHighFrequencyTimerTicks;
__weak unsigned long getRunTimeCounterValue(void)
{
return ulHighFrequencyTimerTicks;
}
/* USER CODE END Application */
